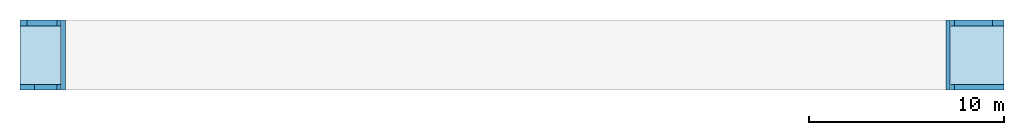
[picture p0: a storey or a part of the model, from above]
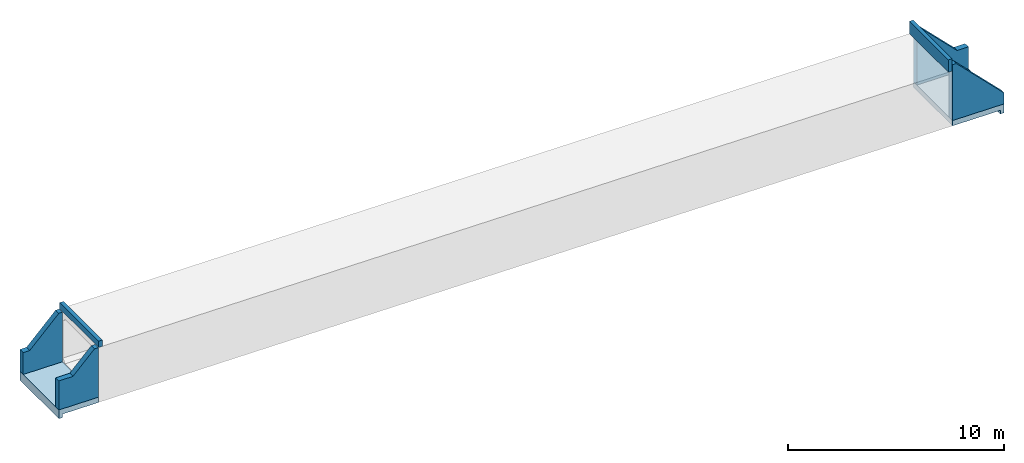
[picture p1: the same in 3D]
Properties of the parts of a building model (IFC2X3)

# File
Description: ViewDefinition [CoordinationView_V2.0]
File name: Numéro de projet
Time: 2022-02-16T18:30:36
Written by: The EXPRESS Data Manager Version 5.02.0100.07 : 28 Aug 2013
Made in: 20190225_1515(x64) - Exporter 19.5.0.0 - Interface alternative d'export 19.5.0.0
Comment: STEP Physical File produced by: The EXPRESS Data Manager Version 5.02.0100.07 : 28 Aug 2013 * Module: EDMstepFileFactory/EDMstandAlone * Creation date: Wed Feb 16 18:30:36 2022 * Host: DESKTOP-B6DTHAK * Database: C:\Users\user\AppData\Local\Temp\{E50413D0-17D4-4E85-9F48-4C108A783ABA}\ifc * Database version: 5507 * Database creation date: Wed Feb 16 18:30:32 2022 * Schema: IFC2X3 * Model: DataRepository.ifc * Model creation date: Wed Feb 16 18:30:32 2022 * Header model: DataRepository.ifc_HeaderModel * Header model creation date: Wed Feb 16 18:30:32 2022 * EDMuser: sdai-user * EDMgroup: sdai-group * License ID and type: 5605 : Permanent license. Expiry date: * EDMstepFileFactory options: 020000

# IfcProject, Numéro de projet
LongName: Nom du projet; Phase: Etat du projet

# IfcSite, Default
RefLatitude: 42, 21, 31, 181945; RefLongitude: -71, -3, -24, -263305; RefElevation: 0 m

# IfcBuilding
Pset_BuildingCommon - NumberOfStoreys: 1

# IfcBuildingStorey: Niveau:Pointe 8 mm, Niveau 153
LongName: Niveau 153; Elevation: 153 m

# IfcSlab: Cadre:Cadre, Cadre:Cadre:205704
In: Niveau 153
Type - PredefinedType: BASESLAB; Material: Béton, C30/37
Type - Pset_SlabCommon - IsExternal: no
Pset_QuantityTakeOff - Reference: Cadre; sets with these values: 2
Pset_SlabCommon - Reference: Cadre

# IfcSlab: Longrine Amont:Longrine Amont, Longrine Amont:Longrine Amont:207729
In: Niveau 153
Type - PredefinedType: BASESLAB; Material: Béton, C30/37
Type - Pset_SlabCommon - IsExternal: no
Pset_QuantityTakeOff - Reference: Longrine Amont; sets with these values: 2
Pset_SlabCommon - Reference: Longrine Amont

# IfcSlab: Longrine Aval:Longrine Aval, Longrine Aval:Longrine Aval:207915
In: Niveau 153
Type - PredefinedType: BASESLAB; Material: Béton, C30/37
Type - Pset_SlabCommon - IsExternal: no
Pset_QuantityTakeOff - Reference: Longrine Aval; sets with these values: 2
Pset_SlabCommon - Reference: Longrine Aval

# IfcSlab: Mur 2 Amont:Mur 2 Amont, Mur 2 Amont:Mur 2 Amont:209048
In: Niveau 153
Type - PredefinedType: BASESLAB; Material: Béton, C30/37
Type - Pset_SlabCommon - IsExternal: no
Pset_QuantityTakeOff - Reference: Mur 2 Amont; sets with these values: 2
Pset_SlabCommon - Reference: Mur 2 Amont

# IfcSlab: Mur Amont:Mur Amont, Mur Amont:Mur Amont:208326
In: Niveau 153
Type - PredefinedType: BASESLAB; Material: Béton, C30/37
Type - Pset_SlabCommon - IsExternal: no
Pset_QuantityTakeOff - Reference: Mur Amont; sets with these values: 2
Pset_SlabCommon - Reference: Mur Amont

# IfcSlab: Mur Nord Aval:Mur Nord Aval, Mur Nord Aval:Mur Nord Aval:210463
In: Niveau 153
Type - PredefinedType: BASESLAB; Material: Béton, C30/37
Type - Pset_SlabCommon - IsExternal: no
Pset_QuantityTakeOff - Reference: Mur Nord Aval; sets with these values: 2
Pset_SlabCommon - Reference: Mur Nord Aval

# IfcSlab: Mur Sud Aval:Mur Sud Aval, Mur Sud Aval:Mur Sud Aval:209902
In: Niveau 153
Type - PredefinedType: BASESLAB; Material: Béton, C30/37
Type - Pset_SlabCommon - IsExternal: no
Pset_QuantityTakeOff - Reference: Mur Sud Aval; sets with these values: 2
Pset_SlabCommon - Reference: Mur Sud Aval

# IfcSlab: Radier Amont:Radier Amont, Radier Amont:Radier Amont:207125
In: Niveau 153
Type - PredefinedType: BASESLAB; Material: Béton, C30/37
Type - Pset_SlabCommon - IsExternal: no
Pset_QuantityTakeOff - Reference: Radier Amont; sets with these values: 2
Pset_SlabCommon - Reference: Radier Amont

# IfcSlab: Radier Aval:Radier Aval, Radier Aval:Radier Aval:207514
In: Niveau 153
Type - PredefinedType: BASESLAB; Material: Béton, C30/37
Type - Pset_SlabCommon - IsExternal: no
Pset_QuantityTakeOff - Reference: Radier Aval; sets with these values: 2
Pset_SlabCommon - Reference: Radier Aval
